One B-rep face of a CAD part: STEP entity #350.
In plain terms, the planar face has unit normal (-1, 0, 0).
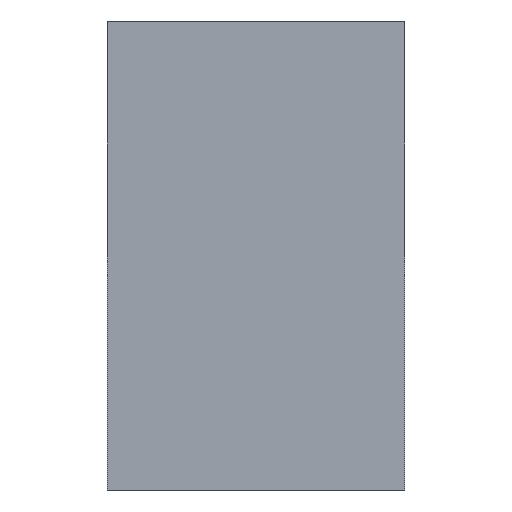
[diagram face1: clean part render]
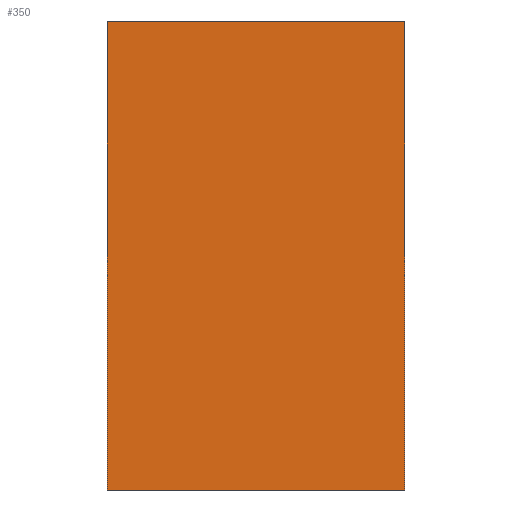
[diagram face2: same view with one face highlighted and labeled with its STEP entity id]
Its self-contained STEP definition (entity closure, numbers rounded to 3 decimals):
#57=CARTESIAN_POINT('Line Origine',(-50.,14.,0.)) ;
#61=CARTESIAN_POINT('Vertex',(-50.,14.,-11.)) ;
#63=CARTESIAN_POINT('Vertex',(-50.,14.,11.)) ;
#320=CARTESIAN_POINT('Axis2P3D Location',(-50.,0.,-0.)) ;
#325=CARTESIAN_POINT('Line Origine',(-50.,7.,-11.)) ;
#329=CARTESIAN_POINT('Vertex',(-50.,0.,-11.)) ;
#332=CARTESIAN_POINT('Line Origine',(-50.,0.,0.)) ;
#336=CARTESIAN_POINT('Vertex',(-50.,0.,11.)) ;
#339=CARTESIAN_POINT('Line Origine',(-50.,7.,11.)) ;
#58=DIRECTION('Vector Direction',(0.,0.,1.)) ;
#321=DIRECTION('Axis2P3D Direction',(1.,0.,-0.)) ;
#322=DIRECTION('Axis2P3D XDirection',(-0.,0.,-1.)) ;
#326=DIRECTION('Vector Direction',(0.,1.,0.)) ;
#333=DIRECTION('Vector Direction',(0.,0.,-1.)) ;
#340=DIRECTION('Vector Direction',(0.,-1.,0.)) ;
#323=AXIS2_PLACEMENT_3D('Plane Axis2P3D',#320,#321,#322) ;
#345=ORIENTED_EDGE('',*,*,#65,.F.) ;
#346=ORIENTED_EDGE('',*,*,#331,.F.) ;
#347=ORIENTED_EDGE('',*,*,#338,.F.) ;
#348=ORIENTED_EDGE('',*,*,#343,.F.) ;
#59=VECTOR('Line Direction',#58,1.) ;
#327=VECTOR('Line Direction',#326,1.) ;
#334=VECTOR('Line Direction',#333,1.) ;
#341=VECTOR('Line Direction',#340,1.) ;
#350=ADVANCED_FACE('761-014100',(#349),#324,.F.) ;
#65=EDGE_CURVE('',#62,#64,#60,.T.) ;
#331=EDGE_CURVE('',#330,#62,#328,.T.) ;
#338=EDGE_CURVE('',#337,#330,#335,.T.) ;
#343=EDGE_CURVE('',#64,#337,#342,.T.) ;
#344=EDGE_LOOP('',(#345,#346,#347,#348)) ;
#349=FACE_OUTER_BOUND('',#344,.T.) ;
#60=LINE('Line',#57,#59) ;
#328=LINE('Line',#325,#327) ;
#335=LINE('Line',#332,#334) ;
#342=LINE('Line',#339,#341) ;
#324=PLANE('Plane',#323) ;
#62=VERTEX_POINT('',#61) ;
#64=VERTEX_POINT('',#63) ;
#330=VERTEX_POINT('',#329) ;
#337=VERTEX_POINT('',#336) ;
